VERSION 5.7 ;
  NOWIREEXTENSIONATPIN ON ;
  DIVIDERCHAR "/" ;
  BUSBITCHARS "[]" ;
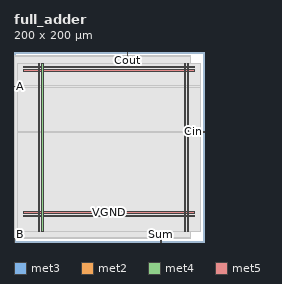
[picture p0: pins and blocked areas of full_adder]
MACRO full_adder
  CLASS BLOCK ;
  FOREIGN full_adder ;
  ORIGIN 0.000 0.000 ;
  SIZE 200.000 BY 200.000 ;
  PIN A
    DIRECTION INPUT ;
    USE SIGNAL ;
    ANTENNAGATEAREA 0.213000 ;
    PORT
      LAYER met3 ;
        RECT 0.000 163.240 4.000 163.840 ;
    END
  END A
  PIN B
    DIRECTION INPUT ;
    USE SIGNAL ;
    ANTENNAGATEAREA 0.159000 ;
    PORT
      LAYER met2 ;
        RECT 0.090 0.000 0.370 4.000 ;
    END
  END B
  PIN Cin
    DIRECTION INPUT ;
    USE SIGNAL ;
    ANTENNAGATEAREA 0.213000 ;
    PORT
      LAYER met3 ;
        RECT 196.000 115.640 200.000 116.240 ;
    END
  END Cin
  PIN Cout
    DIRECTION OUTPUT TRISTATE ;
    USE SIGNAL ;
    ANTENNADIFFAREA 0.795200 ;
    PORT
      LAYER met2 ;
        RECT 119.230 196.000 119.510 200.000 ;
    END
  END Cout
  PIN Sum
    DIRECTION OUTPUT TRISTATE ;
    USE SIGNAL ;
    ANTENNADIFFAREA 0.795200 ;
    PORT
      LAYER met2 ;
        RECT 154.650 0.000 154.930 4.000 ;
    END
  END Sum
  PIN VGND
    DIRECTION INOUT ;
    USE GROUND ;
    PORT
      LAYER met4 ;
        RECT 28.940 10.640 30.540 187.920 ;
    END
    PORT
      LAYER met4 ;
        RECT 182.540 10.640 184.140 187.920 ;
    END
    PORT
      LAYER met5 ;
        RECT 9.880 30.030 190.220 31.630 ;
    END
    PORT
      LAYER met5 ;
        RECT 9.880 183.210 190.220 184.810 ;
    END
  END VGND
  PIN VPWR
    DIRECTION INOUT ;
    USE POWER ;
    PORT
      LAYER met4 ;
        RECT 25.640 10.640 27.240 187.920 ;
    END
    PORT
      LAYER met4 ;
        RECT 179.240 10.640 180.840 187.920 ;
    END
    PORT
      LAYER met5 ;
        RECT 9.880 26.730 190.220 28.330 ;
    END
    PORT
      LAYER met5 ;
        RECT 9.880 179.910 190.220 181.510 ;
    END
  END VPWR
  OBS
      LAYER li1 ;
        RECT 10.120 10.795 189.980 187.765 ;
      LAYER met1 ;
        RECT 0.070 10.640 189.980 187.920 ;
      LAYER met2 ;
        RECT 0.100 195.720 118.950 196.000 ;
        RECT 119.790 195.720 186.210 196.000 ;
        RECT 0.100 4.280 186.210 195.720 ;
        RECT 0.650 4.000 154.370 4.280 ;
        RECT 155.210 4.000 186.210 4.280 ;
      LAYER met3 ;
        RECT 4.000 164.240 196.000 187.845 ;
        RECT 4.400 162.840 196.000 164.240 ;
        RECT 4.000 116.640 196.000 162.840 ;
        RECT 4.000 115.240 195.600 116.640 ;
        RECT 4.000 10.715 196.000 115.240 ;
  END
END full_adder
END LIBRARY

